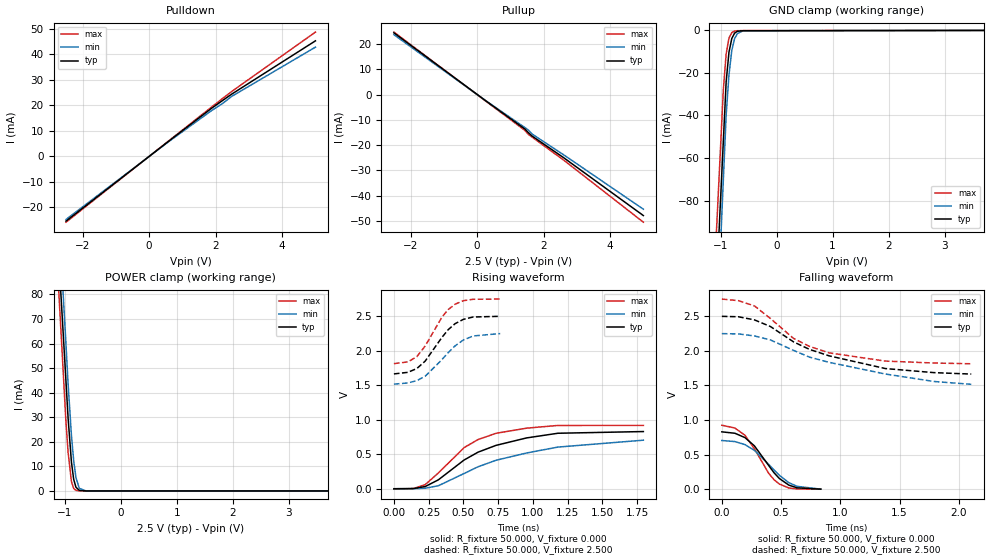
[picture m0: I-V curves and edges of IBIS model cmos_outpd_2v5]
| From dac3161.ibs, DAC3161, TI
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[Model]   cmos_outpd_2v5
Model_type 3-state
Vref=0.000E+00
Rref=1.000E+06
Cref=0.000E+00
Vmeas=1.250E+00
C_comp   1.070E-12   1.070E-12   1.070E-12
[Voltage Range]   2.500E+00   2.250E+00   2.750E+00
[POWER Clamp Reference]   2.500E+00   2.250E+00   2.750E+00
[GND Clamp Reference]   0.000E+00   0.000E+00   0.000E+00
[Pullup Reference]   2.500E+00   2.250E+00   2.750E+00
[Pulldown Reference]   0.000E+00   0.000E+00   0.000E+00
[Temperature Range]   25   85   -40
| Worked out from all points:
|   slope of the pulldown table from 0 to 0.375 V, typ, clamps not added: 98.1 ohm
|   slope of the pullup table from 0 to 0.375 V, typ, clamps not added: 105 ohm
|   GND clamp passes 1 mA (typ) near -0.73 V on its own axis
|   POWER clamp passes 1 mA (typ) near -0.78 V on its own axis
|   rising waveform, R_fixture 50.000, V_fixture 0.000: 20-80 % time 451ps typ, 639ps min, 334ps max; typ from 0.001 V to 0.83 V
|   falling waveform, R_fixture 50.000, V_fixture 0.000: 20-80 % time 223ps typ, 254ps min, 199ps max; typ from 0.83 V to 0.001 V
|   rising waveform, R_fixture 50.000, V_fixture 2.500: 20-80 % time 188ps typ, 215ps min, 173ps max; typ from 1.67 V to 2.5 V
|   falling waveform, R_fixture 50.000, V_fixture 2.500: 20-80 % time 683ps typ, 898ps min, 494ps max; typ from 2.5 V to 1.67 V
[GND Clamp]
-2.5V     -910.4mA   -1.007A    -866.3mA
-950mV    -51.81mA   -69.99mA   -27.77mA
-900mV    -24.11mA   -39.78mA   -11.07mA
-850mV    -10.28mA   -20.91mA   -3.606mA
-800mV    -3.848mA   -9.481mA   -1.049mA
-750mV    -1.297mA   -3.904mA   -310.8uA
-700mV    -414.9uA   -1.507mA   -138.7uA
-600mV    -141uA     -199.2uA   -105.3uA
5V        32.89uA    38.71uA    26.11uA
[Power Clamp]
-2.5V     638.8mA    683.4mA    659.1mA
-1.1V     92.48mA    109.5mA    78.48mA
-1.06V    76.87mA    93.15mA    62.21mA
-1.04V    69.07mA    84.99mA    53.9mA
-980mV    45.52mA    60.64mA    28.82mA
-940mV    29.69mA    43.66mA    15.76mA
-880mV    11.7mA     22.52mA    3.835mA
-840mV    4.741mA    12.31mA    1.012mA
-800mV    1.52mA     5.467mA    230.6uA
-740mV    236.9uA    1.052mA    35.38uA
-620mV    0A         0A         0A
5V        0A         0A         0A
[Pullup]
-2.5V     24.4mA     23.66mA    24.7mA
260mV     -2.479mA   -2.429mA   -2.596mA
1.44V     -13.68mA   -13.1mA    -14.22mA
1.54V     -15.06mA   -14.01mA   -15.74mA
1.66V     -16.49mA   -15.68mA   -16.9mA
2.6V      -24.96mA   -23.82mA   -25.91mA
5V        -47.89mA   -45.37mA   -50.51mA
[Pulldown]
-2.5V     -25.37mA   -24.73mA   -25.79mA
600mV     6.103mA    5.92mA     6.223mA
1.88V     18.92mA    18.01mA    19.4mA
2.2V      21.87mA    20.69mA    22.65mA
2.48V     24.42mA    23.54mA    25.45mA
5V        45.34mA    42.86mA    48.77mA
[Rising Waveform]
R_fixture = 50.000
V_fixture = 0.000
V_fixture_min = 0.000
V_fixture_max = 0.000
|  time   V(typ)   V(min)   V(max)
0s        963.3uV    853.1uV    -5.444mV
140ps     3.78mV     889.3uV    3.877mV
225ps     32.48mV    8.079mV    60.18mV
320ps     130mV      44.29mV    229.7mV
505ps     417.1mV    221.6mV    596.7mV
605ps     530.4mV    318.8mV    713.3mV
735ps     629.6mV    413.6mV    804.5mV
955ps     737.5mV    519.1mV    879mV
1.18ns    805mV      604.5mV    918.1mV
1.795ns   829.7mV    704.5mV    918.7mV
[Falling Waveform]
R_fixture = 50.000
V_fixture = 0.000
V_fixture_min = 0.000
V_fixture_max = 0.000
|  time   V(typ)   V(min)   V(max)
0s        829.7mV    704.5mV    925.3mV
110ps     809.4mV    688.9mV    884.7mV
195ps     746.5mV    645.3mV    780.8mV
275ps     626.8mV    561.2mV    584.9mV
395ps     343.6mV    360.4mV    230.9mV
440ps     239.2mV    278.6mV    138.1mV
485ps     155.5mV    201.9mV    74.99mV
565ps     59.54mV    95.18mV    17.88mV
635ps     20.08mV    41.42mV    2.941mV
835ps     963.3uV    853.1uV    617.2uV
[Rising Waveform]
R_fixture = 50.000
V_fixture = 2.500
V_fixture_min = 2.250
V_fixture_max = 2.750
|  time   V(typ)   V(min)   V(max)
0s        1.665V     1.517V     1.814V
100ps     1.688V     1.534V     1.839V
165ps     1.743V     1.568V     1.915V
225ps     1.851V     1.631V     2.07V
345ps     2.193V     1.871V     2.486V
390ps     2.305V     1.972V     2.596V
440ps     2.393V     2.071V     2.676V
500ps     2.456V     2.157V     2.726V
570ps     2.49V      2.215V     2.747V
765ps     2.5V       2.25V      2.75V
[Falling Waveform]
R_fixture = 50.000
V_fixture = 2.500
V_fixture_min = 2.250
V_fixture_max = 2.750
|  time   V(typ)   V(min)   V(max)
0s        2.5V       2.25V      2.75V
140ps     2.494V     2.246V     2.727V
275ps     2.449V     2.217V     2.651V
410ps     2.353V     2.159V     2.469V
605ps     2.131V     2.008V     2.181V
740ps     2.022V     1.91V      2.065V
905ps     1.929V     1.835V     1.972V
1.38ns    1.745V     1.666V     1.853V
1.79ns    1.686V     1.558V     1.825V
2.105ns   1.665V     1.517V     1.814V
[Ramp]
dV/dt_r   4.9737E-01/4.4920E-10   4.2087E-01/6.3781E-10   5.5450E-01/3.3191E-10
dV/dt_f   5.0099E-01/6.8234E-10   4.3980E-01/8.9773E-10   5.6139E-01/4.9215E-10
R_load = 50
